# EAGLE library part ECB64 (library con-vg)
CONNECTOR male, 64 pins, block, type C, rows AC, grid 5.08 mm

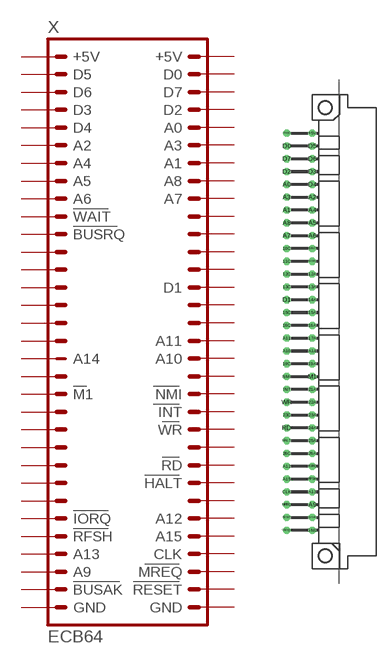
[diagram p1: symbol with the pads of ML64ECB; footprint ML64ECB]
Designator prefix X

## ECB64  [ML64ECB]
10C    nc
11C    nc
12A    nc
12C    nc
13A    nc
13C    nc
14A    nc
15A    nc
15C    nc
16A    nc
16C    nc
17A    nc
19A    nc
19C    nc
21A    nc
22A    nc
23A    nc
23C    nc
24A    nc
25A    nc
26A    nc
26C    nc
+5V  +5V  pwr
+5V@1  +5V  pwr
A0  A0
A1  A1
A2  A2
A3  A3
A4  A4
A5  A5
A6  A6
A7  A7
A8  A8
A9  A9
A10  A10
A11  A11
A12  A12
A13  A13
A14  A14
A15  A15
BUSAK  BUSAK
BUSRQ  BUSRQ
CLK  CLK
D0  D0
D1  D1
D2  D2
D3  D3
D4  D4
D5  D5
D6  D6
D7  D7
GND  GND  pwr
GND@1  GND  pwr
HALT  HALT
INT  INT
IORQ  IORQ
M1  M1
MREQ  MREQ
NMI  NMI
RD  RD
RESET  RESET
RFSH  RFSH
WAIT  WAIT
WR  WR

## Footprint ML64ECB (pad centres in mm)
CONNECTOR male, 64 pins, type C, rows AC, grid 5.08 mm
drill 0.914 octagon: 10C -7.62,16.51; 11C -7.62,13.97; 12A -2.54,11.43; 12C -7.62,11.43; 13A -2.54,8.89; 13C -7.62,8.89; 14A -2.54,6.35; 15A -2.54,3.81; 15C -7.62,3.81; 16A -2.54,1.27; 16C -7.62,1.27; 17A -2.54,-1.27; 19A -2.54,-6.35; 19C -7.62,-6.35; 21A -2.54,-11.43; 22A -2.54,-13.97; 23A -2.54,-16.51; 23C -7.62,-16.51; 24A -2.54,-19.05; 25A -2.54,-21.59; 26A -2.54,-24.13; 26C -7.62,-24.13; +5V -2.54,39.37; +5V@1 -7.62,39.37; A0 -7.62,29.21; A1 -7.62,24.13; A2 -2.54,26.67; A3 -7.62,26.67; A4 -2.54,24.13; A5 -2.54,21.59; A6 -2.54,19.05; A7 -7.62,19.05; A8 -7.62,21.59; A9 -2.54,-34.29; A10 -7.62,-3.81; A11 -7.62,-1.27; A12 -7.62,-26.67; A13 -2.54,-31.75; A14 -2.54,-3.81; A15 -7.62,-29.21; BUSAK -2.54,-36.83; BUSRQ -2.54,13.97; CLK -7.62,-31.75; D0 -7.62,36.83; D1 -7.62,6.35; D2 -7.62,31.75; D3 -2.54,31.75; D4 -2.54,29.21; D5 -2.54,36.83; D6 -2.54,34.29; D7 -7.62,34.29; GND -2.54,-39.37; GND@1 -7.62,-39.37; HALT -7.62,-21.59; INT -7.62,-11.43; IORQ -2.54,-26.67; M1 -2.54,-8.89; MREQ -7.62,-34.29; NMI -7.62,-8.89; RD -7.62,-19.05; RESET -7.62,-36.83; RFSH -2.54,-29.21; WAIT -2.54,16.51; WR -7.62,-13.97
hole 2.794 at 0,44.45
hole 2.794 at 0,-44.45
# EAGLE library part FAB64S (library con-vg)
CONNECTOR female, 64 pins, block, type B, rows AB, grid 2.54 mm

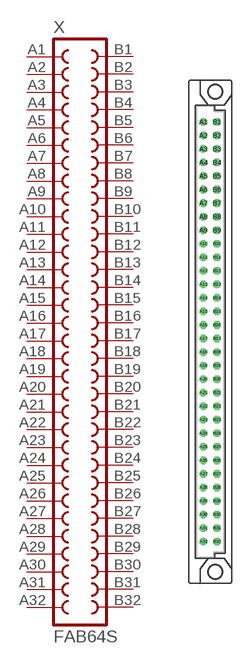
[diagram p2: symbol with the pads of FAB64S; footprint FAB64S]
Designator prefix X

## FAB64S  [FAB64S]
A1  A1  pas
A2  A2  pas
A3  A3  pas
A4  A4  pas
A5  A5  pas
A6  A6  pas
A7  A7  pas
A8  A8  pas
A9  A9  pas
A10  A10  pas
A11  A11  pas
A12  A12  pas
A13  A13  pas
A14  A14  pas
A15  A15  pas
A16  A16  pas
A17  A17  pas
A18  A18  pas
A19  A19  pas
A20  A20  pas
A21  A21  pas
A22  A22  pas
A23  A23  pas
A24  A24  pas
A25  A25  pas
A26  A26  pas
A27  A27  pas
A28  A28  pas
A29  A29  pas
A30  A30  pas
A31  A31  pas
A32  A32  pas
B1  B1  pas
B2  B2  pas
B3  B3  pas
B4  B4  pas
B5  B5  pas
B6  B6  pas
B7  B7  pas
B8  B8  pas
B9  B9  pas
B10  B10  pas
B11  B11  pas
B12  B12  pas
B13  B13  pas
B14  B14  pas
B15  B15  pas
B16  B16  pas
B17  B17  pas
B18  B18  pas
B19  B19  pas
B20  B20  pas
B21  B21  pas
B22  B22  pas
B23  B23  pas
B24  B24  pas
B25  B25  pas
B26  B26  pas
B27  B27  pas
B28  B28  pas
B29  B29  pas
B30  B30  pas
B31  B31  pas
B32  B32  pas

## Footprint FAB64S (pad centres in mm)
CONNECTOR female, 64 pins, type B, rows AB, grid 2.54 mm
drill 0.914 octagon: A1 -1.27,39.37; A2 -1.27,36.83; A3 -1.27,34.29; A4 -1.27,31.75; A5 -1.27,29.21; A6 -1.27,26.67; A7 -1.27,24.13; A8 -1.27,21.59; A9 -1.27,19.05; A10 -1.27,16.51; A11 -1.27,13.97; A12 -1.27,11.43; A13 -1.27,8.89; A14 -1.27,6.35; A15 -1.27,3.81; A16 -1.27,1.27; A17 -1.27,-1.27; A18 -1.27,-3.81; A19 -1.27,-6.35; A20 -1.27,-8.89; A21 -1.27,-11.43; A22 -1.27,-13.97; A23 -1.27,-16.51; A24 -1.27,-19.05; A25 -1.27,-21.59; A26 -1.27,-24.13; A27 -1.27,-26.67; A28 -1.27,-29.21; A29 -1.27,-31.75; A30 -1.27,-34.29; A31 -1.27,-36.83; A32 -1.27,-39.37; B1 1.27,39.37; B2 1.27,36.83; B3 1.27,34.29; B4 1.27,31.75; B5 1.27,29.21; B6 1.27,26.67; B7 1.27,24.13; B8 1.27,21.59; B9 1.27,19.05; B10 1.27,16.51; B11 1.27,13.97; B12 1.27,11.43; B13 1.27,8.89; B14 1.27,6.35; B15 1.27,3.81; B16 1.27,1.27; B17 1.27,-1.27; B18 1.27,-3.81; B19 1.27,-6.35; B20 1.27,-8.89; B21 1.27,-11.43; B22 1.27,-13.97; B23 1.27,-16.51; B24 1.27,-19.05; B25 1.27,-21.59; B26 1.27,-24.13; B27 1.27,-26.67; B28 1.27,-29.21; B29 1.27,-31.75; B30 1.27,-34.29; B31 1.27,-36.83; B32 1.27,-39.37
hole 2.794 at 0.965,-45.009
hole 2.794 at 0.965,45.009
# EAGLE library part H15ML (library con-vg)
CONNECTOR male, 15 high current pins, block, type H, rows DZ

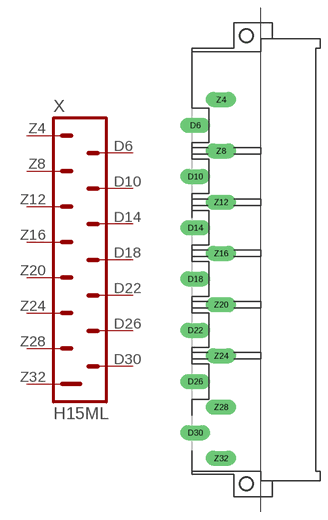
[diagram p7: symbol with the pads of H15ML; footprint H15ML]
Designator prefix X

## H15ML  [H15ML]
D6  D6  pas
D10  D10  pas
D14  D14  pas
D18  D18  pas
D22  D22  pas
D26  D26  pas
D30  D30  pas
Z4  Z4  pas
Z8  Z8  pas
Z12  Z12  pas
Z16  Z16  pas
Z20  Z20  pas
Z24  Z24  pas
Z28  Z28  pas
Z32  Z32  pas

## Footprint H15ML (pad centres in mm)
CONNECTOR male, 15 pins, type H, rows DZ
drill 1.6 pad 3 long: D6 -10.16,26.67; D10 -10.16,16.51; D14 -10.16,6.35; D18 -10.16,-3.81; D22 -10.16,-13.97; D26 -10.16,-24.13; D30 -10.16,-34.29; Z4 -5.08,31.75; Z8 -5.08,21.59; Z12 -5.08,11.43; Z16 -5.08,1.27; Z20 -5.08,-8.89; Z24 -5.08,-19.05; Z28 -5.08,-29.21; Z32 -5.08,-39.37
hole 2.794 at 0,-44.45
hole 2.794 at 0,44.45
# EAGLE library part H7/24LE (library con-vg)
CONNECTOR male, 24 pins + 7 high current pins, single, type H, rows DBZ

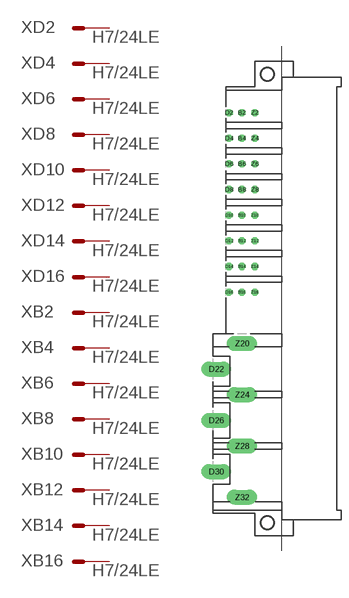
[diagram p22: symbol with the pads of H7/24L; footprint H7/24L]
Designator prefix X; gates D2=M B2=M D4=M B4=M D6=M B6=M D8=M B8=M D10=M B10=M D12=M B12=M D14=M B14=M D16=M B16=M Z2=M Z4=M Z6=M Z8=M Z10=M Z12=M Z14=M Z16=M D22=M D26=M D30=M Z20=M Z24=M Z28=M Z32=MG

## H7/24LE  [H7/24L]
B2  B2:S  pas
B4  B4:S  pas
B6  B6:S  pas
B8  B8:S  pas
B10  B10:S  pas
B12  B12:S  pas
B14  B14:S  pas
B16  B16:S  pas
D2  D2:S  pas
D4  D4:S  pas
D6  D6:S  pas
D8  D8:S  pas
D10  D10:S  pas
D12  D12:S  pas
D14  D14:S  pas
D16  D16:S  pas
D22  D22:S  pas
D26  D26:S  pas
D30  D30:S  pas
Z2  Z2:S  pas
Z4  Z4:S  pas
Z6  Z6:S  pas
Z8  Z8:S  pas
Z10  Z10:S  pas
Z12  Z12:S  pas
Z14  Z14:S  pas
Z16  Z16:S  pas
Z20  Z20:S  pas
Z24  Z24:S  pas
Z28  Z28:S  pas
Z32  Z32:S  pas

## Footprint H7/24L (pad centres in mm)
CONNECTOR male, 24 pins + 7 high current, type H7F24, rows DBZ
drill 0.914 octagon: B2 -5.08,36.83; B4 -5.08,31.75; B6 -5.08,26.67; B8 -5.08,21.59; B10 -5.08,16.51; B12 -5.08,11.43; B14 -5.08,6.35; B16 -5.08,1.27; D2 -7.62,36.83; D4 -7.62,31.75; D6 -7.62,26.67; D8 -7.62,21.59; D10 -7.62,16.51; D12 -7.62,11.43; D14 -7.62,6.35; D16 -7.62,1.27; Z2 -2.54,36.83; Z4 -2.54,31.75; Z6 -2.54,26.67; Z8 -2.54,21.59; Z10 -2.54,16.51; Z12 -2.54,11.43; Z14 -2.54,6.35; Z16 -2.54,1.27
drill 1.6 pad 3 long: D22 -10.16,-13.97; D26 -10.16,-24.13; D30 -10.16,-34.29; Z20 -5.08,-8.89; Z24 -5.08,-19.05; Z28 -5.08,-29.21; Z32 -5.08,-39.37
hole 2.794 at 0,-44.45
hole 2.794 at 0,44.45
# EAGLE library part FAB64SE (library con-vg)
CONNECTOR female, 64 pins, single, type B, rows AB, grid 2.54 mm

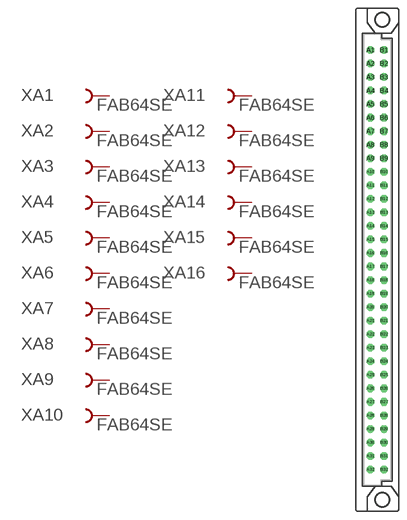
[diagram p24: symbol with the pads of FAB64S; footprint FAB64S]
Designator prefix X; gates A1=F A2=F A3=F A4=F A5=F A6=F A7=F A8=F A9=F A10=F A11=F A12=F A13=F A14=F A15=F A16=F A17=F A18=F A19=F A20=F A21=F A22=F A23=F A24=F A25=F A26=F A27=F A28=F A29=F A30=F A31=F A32=F B1=F B2=F B3=F B4=F B5=F B6=F B7=F B8=F B9=F B10=F B11=F B12=F B13=F B14=F B15=F B16=F B17=F B18=F B19=F B20=F B21=F B22=F B23=F B24=F B25=F B26=F B27=F B28=F B29=F B30=F B31=F B32=F

## FAB64SE  [FAB64S]
A1  A1:B  pas
A2  A2:B  pas
A3  A3:B  pas
A4  A4:B  pas
A5  A5:B  pas
A6  A6:B  pas
A7  A7:B  pas
A8  A8:B  pas
A9  A9:B  pas
A10  A10:B  pas
A11  A11:B  pas
A12  A12:B  pas
A13  A13:B  pas
A14  A14:B  pas
A15  A15:B  pas
A16  A16:B  pas
A17  A17:B  pas
A18  A18:B  pas
A19  A19:B  pas
A20  A20:B  pas
A21  A21:B  pas
A22  A22:B  pas
A23  A23:B  pas
A24  A24:B  pas
A25  A25:B  pas
A26  A26:B  pas
A27  A27:B  pas
A28  A28:B  pas
A29  A29:B  pas
A30  A30:B  pas
A31  A31:B  pas
A32  A32:B  pas
B1  B1:B  pas
B2  B2:B  pas
B3  B3:B  pas
B4  B4:B  pas
B5  B5:B  pas
B6  B6:B  pas
B7  B7:B  pas
B8  B8:B  pas
B9  B9:B  pas
B10  B10:B  pas
B11  B11:B  pas
B12  B12:B  pas
B13  B13:B  pas
B14  B14:B  pas
B15  B15:B  pas
B16  B16:B  pas
B17  B17:B  pas
B18  B18:B  pas
B19  B19:B  pas
B20  B20:B  pas
B21  B21:B  pas
B22  B22:B  pas
B23  B23:B  pas
B24  B24:B  pas
B25  B25:B  pas
B26  B26:B  pas
B27  B27:B  pas
B28  B28:B  pas
B29  B29:B  pas
B30  B30:B  pas
B31  B31:B  pas
B32  B32:B  pas

## Footprint FAB64S (pad centres in mm)
CONNECTOR female, 64 pins, type B, rows AB, grid 2.54 mm
drill 0.914 octagon: A1 -1.27,39.37; A2 -1.27,36.83; A3 -1.27,34.29; A4 -1.27,31.75; A5 -1.27,29.21; A6 -1.27,26.67; A7 -1.27,24.13; A8 -1.27,21.59; A9 -1.27,19.05; A10 -1.27,16.51; A11 -1.27,13.97; A12 -1.27,11.43; A13 -1.27,8.89; A14 -1.27,6.35; A15 -1.27,3.81; A16 -1.27,1.27; A17 -1.27,-1.27; A18 -1.27,-3.81; A19 -1.27,-6.35; A20 -1.27,-8.89; A21 -1.27,-11.43; A22 -1.27,-13.97; A23 -1.27,-16.51; A24 -1.27,-19.05; A25 -1.27,-21.59; A26 -1.27,-24.13; A27 -1.27,-26.67; A28 -1.27,-29.21; A29 -1.27,-31.75; A30 -1.27,-34.29; A31 -1.27,-36.83; A32 -1.27,-39.37; B1 1.27,39.37; B2 1.27,36.83; B3 1.27,34.29; B4 1.27,31.75; B5 1.27,29.21; B6 1.27,26.67; B7 1.27,24.13; B8 1.27,21.59; B9 1.27,19.05; B10 1.27,16.51; B11 1.27,13.97; B12 1.27,11.43; B13 1.27,8.89; B14 1.27,6.35; B15 1.27,3.81; B16 1.27,1.27; B17 1.27,-1.27; B18 1.27,-3.81; B19 1.27,-6.35; B20 1.27,-8.89; B21 1.27,-11.43; B22 1.27,-13.97; B23 1.27,-16.51; B24 1.27,-19.05; B25 1.27,-21.59; B26 1.27,-24.13; B27 1.27,-26.67; B28 1.27,-29.21; B29 1.27,-31.75; B30 1.27,-34.29; B31 1.27,-36.83; B32 1.27,-39.37
hole 2.794 at 0.965,-45.009
hole 2.794 at 0.965,45.009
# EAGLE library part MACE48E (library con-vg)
CONNECTOR male, 48 pins, single, type E, rows ACE, grid 5.08 mm

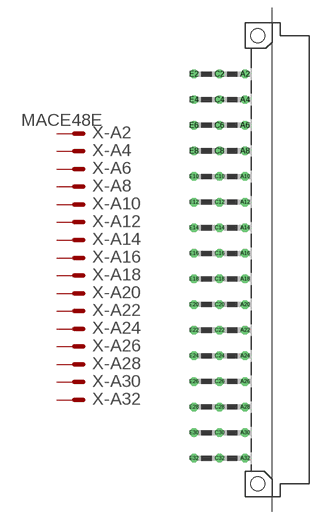
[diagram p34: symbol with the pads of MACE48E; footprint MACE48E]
Designator prefix X; gates -A2=MVAL -A4=MAL -A6=MAL -A8=MAL -A10=MAL -A12=MAL -A14=MAL -A16=MAL -A18=MAL -A20=MAL -A22=MAL -A24=MAL -A26=MAL -A28=MAL -A30=MAL -A32=MAL -C2=MVAL -C4=MAL -C6=MAL -C8=MAL -C10=MAL -C12=MAL -C14=MAL -C16=MAL -C18=MAL -C20=MAL -C22=MAL -C24=MAL -C26=MAL -C28=MAL -C30=MAL -C32=MAL -E2=MVAL -E4=MAL -E6=MAL -E8=MAL -E10=MAL -E12=MAL -E14=MAL -E16=MAL -E18=MAL -E20=MAL -E22=MAL -E24=MAL -E26=MAL -E28=MAL -E30=MAL -E32=MAL

## MACE48E  [MACE48E]
A2  -A2:S  pas
A4  -A4:S  pas
A6  -A6:S  pas
A8  -A8:S  pas
A10  -A10:S  pas
A12  -A12:S  pas
A14  -A14:S  pas
A16  -A16:S  pas
A18  -A18:S  pas
A20  -A20:S  pas
A22  -A22:S  pas
A24  -A24:S  pas
A26  -A26:S  pas
A28  -A28:S  pas
A30  -A30:S  pas
A32  -A32:S  pas
C2  -C2:S  pas
C4  -C4:S  pas
C6  -C6:S  pas
C8  -C8:S  pas
C10  -C10:S  pas
C12  -C12:S  pas
C14  -C14:S  pas
C16  -C16:S  pas
C18  -C18:S  pas
C20  -C20:S  pas
C22  -C22:S  pas
C24  -C24:S  pas
C26  -C26:S  pas
C28  -C28:S  pas
C30  -C30:S  pas
C32  -C32:S  pas
E2  -E2:S  pas
E4  -E4:S  pas
E6  -E6:S  pas
E8  -E8:S  pas
E10  -E10:S  pas
E12  -E12:S  pas
E14  -E14:S  pas
E16  -E16:S  pas
E18  -E18:S  pas
E20  -E20:S  pas
E22  -E22:S  pas
E24  -E24:S  pas
E26  -E26:S  pas
E28  -E28:S  pas
E30  -E30:S  pas
E32  -E32:S  pas

## Footprint MACE48E (pad centres in mm)
CONNECTOR male, 48 pins, type E, rows ACE, grid 5.08 mm
drill 1.118 octagon: A2 -2.54,36.83; A4 -2.54,31.75; A6 -2.54,26.67; A8 -2.54,21.59; A10 -2.54,16.51; A12 -2.54,11.43; A14 -2.54,6.35; A16 -2.54,1.27; A18 -2.54,-3.81; A20 -2.54,-8.89; A22 -2.54,-13.97; A24 -2.54,-19.05; A26 -2.54,-24.13; A28 -2.54,-29.21; A30 -2.54,-34.29; A32 -2.54,-39.37; C2 -7.62,36.83; C4 -7.62,31.75; C6 -7.62,26.67; C8 -7.62,21.59; C10 -7.62,16.51; C12 -7.62,11.43; C14 -7.62,6.35; C16 -7.62,1.27; C18 -7.62,-3.81; C20 -7.62,-8.89; C22 -7.62,-13.97; C24 -7.62,-19.05; C26 -7.62,-24.13; C28 -7.62,-29.21; C30 -7.62,-34.29; C32 -7.62,-39.37; E2 -12.7,36.83; E4 -12.7,31.75; E6 -12.7,26.67; E8 -12.7,21.59; E10 -12.7,16.51; E12 -12.7,11.43; E14 -12.7,6.35; E16 -12.7,1.27; E18 -12.7,-3.81; E20 -12.7,-8.89; E22 -12.7,-13.97; E24 -12.7,-19.05; E26 -12.7,-24.13; E28 -12.7,-29.21; E30 -12.7,-34.29; E32 -12.7,-39.37
hole 2.794 at 0,44.45
hole 2.794 at 0,-44.45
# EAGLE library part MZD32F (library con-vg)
CONNECTOR male, 32 pins, single, type F, rows BZ, grid 5.08 mm

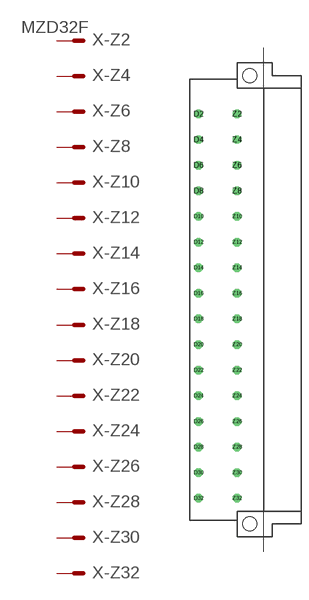
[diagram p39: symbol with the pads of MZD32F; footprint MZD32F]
Designator prefix X; gates -Z2=MVAL -Z4=MAL -Z6=MAL -Z8=MAL -Z10=MAL -Z12=MAL -Z14=MAL -Z16=MAL -Z18=MAL -Z20=MAL -Z22=MAL -Z24=MAL -Z26=MAL -Z28=MAL -Z30=MAL -Z32=MAL -D2=MVAL -D4=MAL -D6=MAL -D8=MAL -D10=MAL -D12=MAL -D14=MAL -D16=MAL -D18=MAL -D20=MAL -D22=MAL -D24=MAL -D26=MAL -D28=MAL -D30=MAL -D32=MAL

## MZD32F  [MZD32F]
D2  -D2:S  pas
D4  -D4:S  pas
D6  -D6:S  pas
D8  -D8:S  pas
D10  -D10:S  pas
D12  -D12:S  pas
D14  -D14:S  pas
D16  -D16:S  pas
D18  -D18:S  pas
D20  -D20:S  pas
D22  -D22:S  pas
D24  -D24:S  pas
D26  -D26:S  pas
D28  -D28:S  pas
D30  -D30:S  pas
D32  -D32:S  pas
Z2  -Z2:S  pas
Z4  -Z4:S  pas
Z6  -Z6:S  pas
Z8  -Z8:S  pas
Z10  -Z10:S  pas
Z12  -Z12:S  pas
Z14  -Z14:S  pas
Z16  -Z16:S  pas
Z18  -Z18:S  pas
Z20  -Z20:S  pas
Z22  -Z22:S  pas
Z24  -Z24:S  pas
Z26  -Z26:S  pas
Z28  -Z28:S  pas
Z30  -Z30:S  pas
Z32  -Z32:S  pas

## Footprint MZD32F (pad centres in mm)
CONNECTOR male, 32 pins, type F, rows DZ, grid 7.62
drill 1.118 octagon: D2 -10.16,36.83; D4 -10.16,31.75; D6 -10.16,26.67; D8 -10.16,21.59; D10 -10.16,16.51; D12 -10.16,11.43; D14 -10.16,6.35; D16 -10.16,1.27; D18 -10.16,-3.81; D20 -10.16,-8.89; D22 -10.16,-13.97; D24 -10.16,-19.05; D26 -10.16,-24.13; D28 -10.16,-29.21; D30 -10.16,-34.29; D32 -10.16,-39.37; Z2 -2.54,36.83; Z4 -2.54,31.75; Z6 -2.54,26.67; Z8 -2.54,21.59; Z10 -2.54,16.51; Z12 -2.54,11.43; Z14 -2.54,6.35; Z16 -2.54,1.27; Z18 -2.54,-3.81; Z20 -2.54,-8.89; Z22 -2.54,-13.97; Z24 -2.54,-19.05; Z26 -2.54,-24.13; Z28 -2.54,-29.21; Z30 -2.54,-34.29; Z32 -2.54,-39.37
hole 2.794 at 0,44.45
hole 2.794 at 0,-44.45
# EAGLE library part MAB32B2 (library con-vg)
CONNECTOR male, 32 pins, single, type B/2, rows AB, grid 2.54 mm

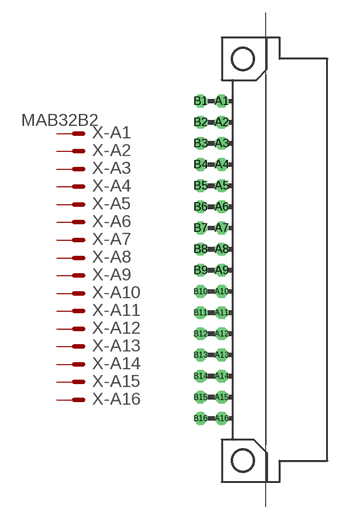
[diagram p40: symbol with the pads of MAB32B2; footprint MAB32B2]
Designator prefix X; gates -A1=MVAL -A2=MAL -A3=MAL -A4=MAL -A5=MAL -A6=MAL -A7=MAL -A8=MAL -A9=MAL -A10=MAL -A11=MAL -A12=MAL -A13=MAL -A14=MAL -A15=MAL -A16=MAL -B1=MVAL -B2=MAL -B3=MAL -B4=MAL -B5=MAL -B6=MAL -B7=MAL -B8=MAL -B9=MAL -B10=MAL -B11=MAL -B12=MAL -B13=MAL -B14=MAL -B15=MAL -B16=MAL

## MAB32B2  [MAB32B2]
A1  -A1:S  pas
A2  -A2:S  pas
A3  -A3:S  pas
A4  -A4:S  pas
A5  -A5:S  pas
A6  -A6:S  pas
A7  -A7:S  pas
A8  -A8:S  pas
A9  -A9:S  pas
A10  -A10:S  pas
A11  -A11:S  pas
A12  -A12:S  pas
A13  -A13:S  pas
A14  -A14:S  pas
A15  -A15:S  pas
A16  -A16:S  pas
B1  -B1:S  pas
B2  -B2:S  pas
B3  -B3:S  pas
B4  -B4:S  pas
B5  -B5:S  pas
B6  -B6:S  pas
B7  -B7:S  pas
B8  -B8:S  pas
B9  -B9:S  pas
B10  -B10:S  pas
B11  -B11:S  pas
B12  -B12:S  pas
B13  -B13:S  pas
B14  -B14:S  pas
B15  -B15:S  pas
B16  -B16:S  pas

## Footprint MAB32B2 (pad centres in mm)
CONNECTOR male, 32 pins, type B/2, rows AB, grid 2.54 mm
drill 1.016 octagon: A1 -2.54,19.05; A2 -2.54,16.51; A3 -2.54,13.97; A4 -2.54,11.43; A5 -2.54,8.89; A6 -2.54,6.35; A7 -2.54,3.81; A8 -2.54,1.27; A9 -2.54,-1.27; A10 -2.54,-3.81; A11 -2.54,-6.35; A12 -2.54,-8.89; A13 -2.54,-11.43; A14 -2.54,-13.97; A15 -2.54,-16.51; A16 -2.54,-19.05; B1 -5.08,19.05; B2 -5.08,16.51; B3 -5.08,13.97; B4 -5.08,11.43; B5 -5.08,8.89; B6 -5.08,6.35; B7 -5.08,3.81; B8 -5.08,1.27; B9 -5.08,-1.27; B10 -5.08,-3.81; B11 -5.08,-6.35; B12 -5.08,-8.89; B13 -5.08,-11.43; B14 -5.08,-13.97; B15 -5.08,-16.51; B16 -5.08,-19.05
hole 2.794 at 0,24.13
hole 2.794 at 0,-24.13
